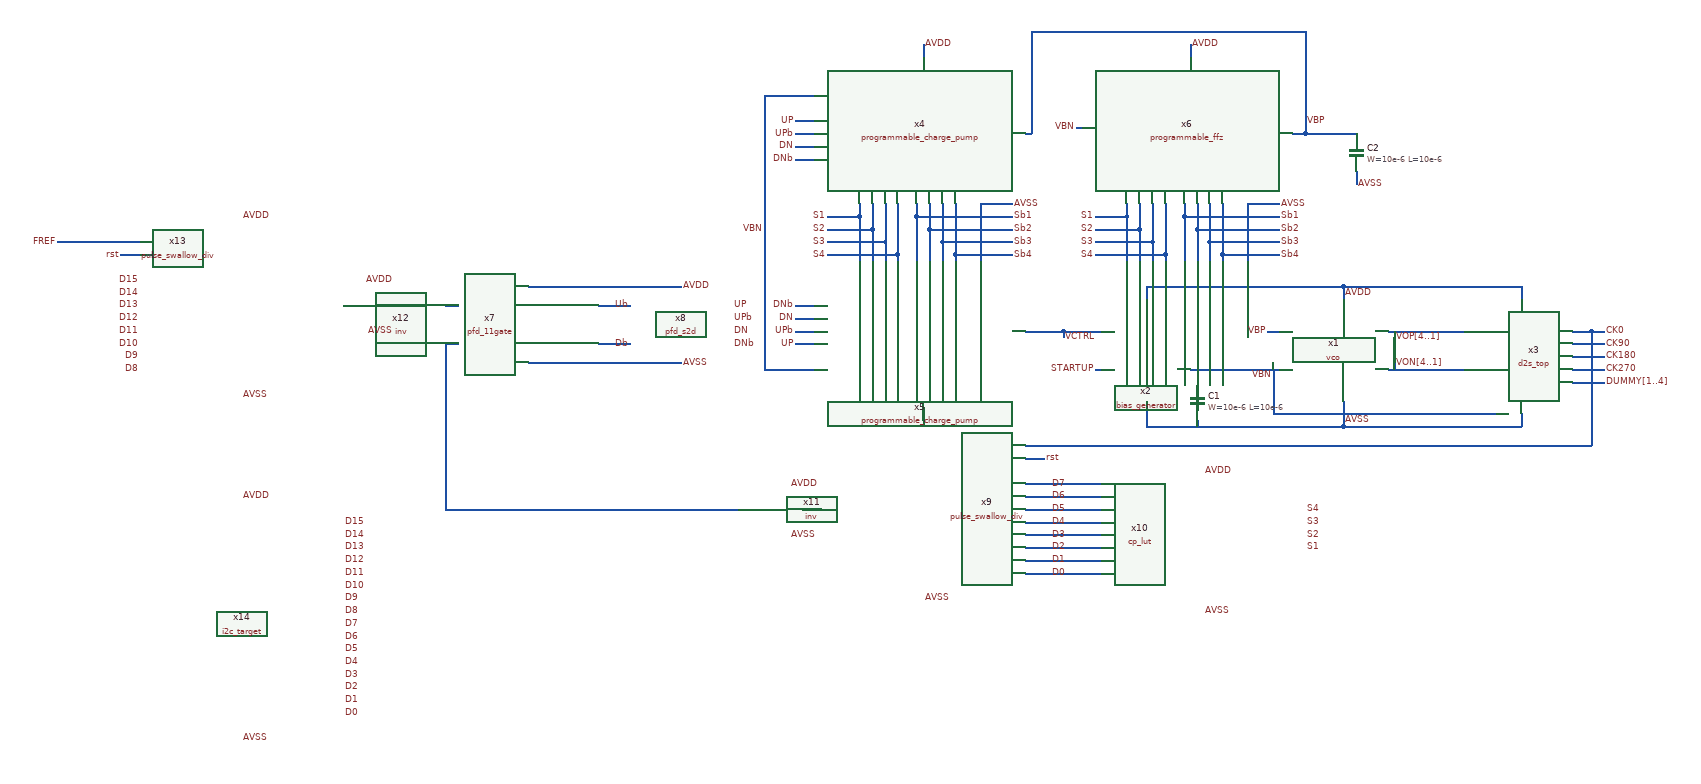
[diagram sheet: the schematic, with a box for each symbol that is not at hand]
v {xschem version=3.4.8RC file_version=1.3}
G {}
K {}
V {}
S {}
F {}
E {}
N 1640 -770 1700 -770 {lab=VCTRL}
N 1910 -710 1980 -710 {lab=VBN}
N 1970 -710 1970 -690 {lab=VBN}
N 2080 -660 2080 -620 {lab=AVSS}
N 1840 -620 2080 -620 {lab=AVSS}
N 1770 -660 1770 -620 {lab=AVSS}
N 2080 -840 2080 -820 {lab=AVDD}
N 1770 -840 1770 -820 {lab=AVDD}
N 1690 -710 1700 -710 {lab=STARTUP}
N 1840 -840 2080 -840 {lab=AVDD}
N 1630 -770 1640 -770 {lab=VCTRL}
N 1620 -770 1630 -770 {lab=VCTRL}
N 1960 -770 1980 -770 {lab=VBP}
N 1640 -770 1640 -760 {lab=VCTRL}
N 2150 -770 2270 -770 {lab=VOP[4..1]}
N 2150 -710 2270 -710 {lab=VON[4..1]}
N 2160 -720 2160 -710 {lab=VON[4..1]}
N 2160 -770 2160 -760 {lab=VOP[4..1]}
N 2360 -840 2360 -820 {lab=AVDD}
N 2080 -840 2360 -840 {lab=AVDD}
N 2360 -640 2360 -620 {lab=AVSS}
N 2080 -620 2360 -620 {lab=AVSS}
N 1770 -620 1840 -620 {lab=AVSS}
N 1850 -630 1850 -620 {lab=AVSS}
N 1840 -710 1910 -710 {lab=VBN}
N 1850 -710 1850 -690 {lab=VBN}
N 1970 -690 1970 -640 {lab=VBN}
N 1970 -640 2320 -640 {lab=VBN}
N 1770 -840 1840 -840 {lab=AVDD}
N 1270 -950 1320 -950 {lab=S1}
N 1270 -930 1340 -930 {lab=S2}
N 1270 -910 1360 -910 {lab=S3}
N 1270 -890 1380 -890 {lab=S4}
N 1510 -970 1560 -970 {lab=AVSS}
N 1470 -890 1560 -890 {lab=Sb4}
N 1450 -910 1560 -910 {lab=Sb3}
N 1430 -930 1560 -930 {lab=Sb2}
N 1410 -950 1560 -950 {lab=Sb1}
N 1230 -1140 1250 -1140 {lab=VBN}
N 1230 -710 1250 -710 {lab=VBN}
N 1220 -1040 1250 -1040 {lab=DNb}
N 1220 -1080 1250 -1080 {lab=UPb}
N 1220 -1060 1250 -1060 {lab=DN}
N 1220 -1100 1250 -1100 {lab=UP}
N 1220 -810 1250 -810 {lab=DNb}
N 1220 -770 1250 -770 {lab=UPb}
N 1220 -790 1250 -790 {lab=DN}
N 1220 -750 1250 -750 {lab=UP}
N 1420 -1220 1420 -1200 {lab=AVDD}
N 1420 -650 1420 -630 {lab=AVDD}
N 1510 -970 1510 -880 {lab=AVSS}
N 1170 -1140 1230 -1140 {lab=VBN}
N 1170 -1140 1170 -710 {lab=VBN}
N 1170 -710 1230 -710 {lab=VBN}
N 2020 -1160 2020 -1080 {lab=VBP}
N 1410 -950 1410 -880 {lab=Sb1}
N 1430 -930 1430 -880 {lab=Sb2}
N 1450 -910 1450 -880 {lab=Sb3}
N 1470 -890 1470 -880 {lab=Sb4}
N 1320 -950 1320 -880 {lab=S1}
N 1340 -930 1340 -880 {lab=S2}
N 1360 -910 1360 -880 {lab=S3}
N 1380 -890 1380 -880 {lab=S4}
N 1380 -970 1380 -890 {lab=S4}
N 1360 -970 1360 -910 {lab=S3}
N 1340 -970 1340 -930 {lab=S2}
N 1320 -970 1320 -950 {lab=S1}
N 1410 -970 1410 -950 {lab=Sb1}
N 1430 -970 1430 -930 {lab=Sb2}
N 1450 -970 1450 -910 {lab=Sb3}
N 1470 -970 1470 -890 {lab=Sb4}
N 1690 -950 1740 -950 {lab=S1}
N 1690 -930 1760 -930 {lab=S2}
N 1690 -910 1780 -910 {lab=S3}
N 1690 -890 1800 -890 {lab=S4}
N 1930 -970 1980 -970 {lab=AVSS}
N 1890 -890 1980 -890 {lab=Sb4}
N 1870 -910 1980 -910 {lab=Sb3}
N 1850 -930 1980 -930 {lab=Sb2}
N 1830 -950 1980 -950 {lab=Sb1}
N 1930 -970 1930 -880 {lab=AVSS}
N 1830 -950 1830 -880 {lab=Sb1}
N 1850 -930 1850 -880 {lab=Sb2}
N 1870 -910 1870 -880 {lab=Sb3}
N 1890 -890 1890 -880 {lab=Sb4}
N 1740 -950 1740 -880 {lab=S1}
N 1760 -930 1760 -880 {lab=S2}
N 1780 -910 1780 -880 {lab=S3}
N 1800 -890 1800 -880 {lab=S4}
N 1800 -970 1800 -890 {lab=S4}
N 1780 -970 1780 -910 {lab=S3}
N 1760 -970 1760 -930 {lab=S2}
N 1740 -970 1740 -950 {lab=S1}
N 1830 -970 1830 -950 {lab=Sb1}
N 1850 -970 1850 -930 {lab=Sb2}
N 1870 -970 1870 -910 {lab=Sb3}
N 1890 -970 1890 -890 {lab=Sb4}
N 2000 -1080 2020 -1080 {lab=VBP}
N 1590 -1090 1590 -1080 {lab=VBP}
N 1580 -1080 1590 -1080 {lab=VBP}
N 2020 -1240 2020 -1220 {lab=VBP}
N 1590 -1240 2020 -1240 {lab=VBP}
N 1590 -1240 1590 -1090 {lab=VBP}
N 1840 -1220 1840 -1200 {lab=AVDD}
N 1660 -1090 1670 -1090 {lab=VBN}
N 2020 -1220 2020 -1160 {lab=VBP}
N 1580 -770 1620 -770 {lab=VCTRL}
N 910 -810 960 -810 {lab=Ub}
N 910 -750 960 -750 {lab=Db}
N 800 -840 1040 -840 {lab=AVDD}
N 800 -720 1040 -720 {lab=AVSS}
N 1580 -590 1610 -590 {lab=CK0}
N 1580 -570 1610 -570 {lab=rst}
N 1580 -530 1700 -530 {lab=D7}
N 1580 -510 1700 -510 {lab=D6}
N 1580 -490 1700 -490 {lab=D5}
N 1580 -470 1700 -470 {lab=D4}
N 1580 -450 1700 -450 {lab=D3}
N 1580 -430 1700 -430 {lab=D2}
N 1580 -410 1700 -410 {lab=D1}
N 1580 -390 1700 -390 {lab=D0}
N 1610 -590 2470 -590 {lab=CK0}
N 2470 -770 2470 -590 {lab=CK0}
N 2440 -770 2470 -770 {lab=CK0}
N 1230 -490 1260 -490 {lab=#net1}
N 670 -490 1130 -490 {lab=#net2}
N 670 -750 670 -490 {lab=#net2}
N 670 -750 690 -750 {lab=#net2}
N 670 -810 690 -810 {lab=#net3}
N 2020 -1080 2100 -1080 {lab=VBP}
N 2100 -1020 2100 -1000 {lab=AVSS}
N 510 -810 570 -810 {lab=#net4}
N 60 -910 190 -910 {lab=FREF}
N 160 -890 190 -890 {lab=rst}
N 2440 -750 2490 -750 {lab=CK90}
N 2470 -770 2490 -770 {lab=CK0}
N 2440 -730 2490 -730 {lab=CK180}
N 2440 -710 2490 -710 {lab=CK270}
N 2440 -690 2490 -690 {lab=DUMMY[1..4]}
C {libs/core_analog/vco/vco.sym} 2080 -740 0 0 {name=x1}
C {libs/core_analog/bias_generator/bias_generator.sym} 1770 -740 0 0 {name=x2}
C {lab_pin.sym} 2080 -630 0 1 {name=p9 sig_type=std_logic lab=AVSS}
C {lab_pin.sym} 1690 -710 0 0 {name=p11 sig_type=std_logic lab=STARTUP}
C {lab_pin.sym} 2160 -760 2 0 {name=p13 sig_type=std_logic lab=VOP[4..1]}
C {lab_pin.sym} 2160 -720 2 0 {name=p14 sig_type=std_logic lab=VON[4..1]}
C {lab_pin.sym} 2080 -830 0 1 {name=p41 sig_type=std_logic lab=AVDD}
C {lab_pin.sym} 1970 -700 0 0 {name=p38 sig_type=std_logic lab=VBN}
C {lab_pin.sym} 1960 -770 0 0 {name=p39 sig_type=std_logic lab=VBP}
C {lab_pin.sym} 1640 -760 0 1 {name=p42 sig_type=std_logic lab=VCTRL}
C {symbols/cap_mim_2f0fF.sym} 1850 -660 2 1 {name=C1
W=10e-6
L=10e-6
model=cap_mim_2f0fF
spiceprefix=X
m=50}
C {libs/core_analog/d2s_top/d2s_top.sym} 2360 -740 0 0 {name=x3}
C {lab_pin.sym} 1170 -930 0 0 {name=p1 sig_type=std_logic lab=VBN}
C {lab_pin.sym} 1420 -1220 0 1 {name=p43 sig_type=std_logic lab=AVDD}
C {lab_wire.sym} 1220 -1100 0 0 {name=p47 sig_type=std_logic lab=UP}
C {lab_wire.sym} 1220 -1060 0 0 {name=p48 sig_type=std_logic lab=DN}
C {lab_wire.sym} 1220 -1040 0 0 {name=p49 sig_type=std_logic lab=DNb}
C {lab_wire.sym} 1220 -1080 0 0 {name=p50 sig_type=std_logic lab=UPb}
C {lab_wire.sym} 1220 -750 2 1 {name=p51 sig_type=std_logic lab=UP}
C {lab_wire.sym} 1220 -790 2 1 {name=p52 sig_type=std_logic lab=DN}
C {lab_wire.sym} 1220 -810 2 1 {name=p53 sig_type=std_logic lab=DNb}
C {lab_wire.sym} 1220 -770 2 1 {name=p54 sig_type=std_logic lab=UPb}
C {lab_pin.sym} 1420 -640 2 0 {name=p17 sig_type=std_logic lab=AVDD}
C {lab_pin.sym} 1560 -970 0 1 {name=p46 sig_type=std_logic lab=AVSS}
C {lab_pin.sym} 1270 -950 2 1 {name=p59 sig_type=std_logic lab=S1}
C {lab_pin.sym} 1270 -930 2 1 {name=p60 sig_type=std_logic lab=S2}
C {lab_pin.sym} 1270 -910 2 1 {name=p61 sig_type=std_logic lab=S3}
C {lab_pin.sym} 1270 -890 2 1 {name=p62 sig_type=std_logic lab=S4}
C {lab_pin.sym} 1980 -970 0 1 {name=p63 sig_type=std_logic lab=AVSS}
C {lab_pin.sym} 1980 -950 2 0 {name=p64 sig_type=std_logic lab=Sb1}
C {lab_pin.sym} 1690 -950 2 1 {name=p68 sig_type=std_logic lab=S1}
C {lab_pin.sym} 1690 -930 2 1 {name=p69 sig_type=std_logic lab=S2}
C {lab_pin.sym} 1690 -910 2 1 {name=p70 sig_type=std_logic lab=S3}
C {lab_pin.sym} 1690 -890 2 1 {name=p71 sig_type=std_logic lab=S4}
C {lab_pin.sym} 2020 -1100 0 1 {name=p72 sig_type=std_logic lab=VBP}
C {lab_pin.sym} 1840 -1220 0 1 {name=p73 sig_type=std_logic lab=AVDD}
C {lab_pin.sym} 1660 -1090 0 0 {name=p74 sig_type=std_logic lab=VBN}
C {lab_pin.sym} 1980 -930 2 0 {name=p65 sig_type=std_logic lab=Sb2}
C {lab_pin.sym} 1980 -910 2 0 {name=p66 sig_type=std_logic lab=Sb3}
C {lab_pin.sym} 1980 -890 2 0 {name=p67 sig_type=std_logic lab=Sb4}
C {lab_pin.sym} 1560 -950 2 0 {name=p105 sig_type=std_logic lab=Sb1}
C {lab_pin.sym} 1560 -930 2 0 {name=p106 sig_type=std_logic lab=Sb2}
C {lab_pin.sym} 1560 -910 2 0 {name=p107 sig_type=std_logic lab=Sb3}
C {lab_pin.sym} 1560 -890 2 0 {name=p109 sig_type=std_logic lab=Sb4}
C {libs/core_analog/programmable_charge_pump/programmable_charge_pump.sym} 1420 -1080 0 0 {name=x4}
C {libs/core_analog/programmable_charge_pump/programmable_charge_pump.sym} 1420 -770 2 1 {name=x5}
C {libs/core_analog/programmable_ffz/programmable_ffz.sym} 1840 -1090 0 0 {name=x6}
C {libs/core_analog/pfd/pfd_11gate.sym} 800 -780 0 0 {name=x7}
C {lab_wire.sym} 960 -810 0 0 {name=p4 sig_type=std_logic lab=Ub}
C {lab_wire.sym} 960 -750 0 0 {name=p5 sig_type=std_logic lab=Db}
C {libs/core_analog/pfd_s2d/pfd_s2d.sym} 1040 -780 0 0 {name=x8}
C {lab_wire.sym} 1120 -810 0 1 {name=p10 sig_type=std_logic lab=UP}
C {lab_wire.sym} 1120 -770 0 1 {name=p2 sig_type=std_logic lab=DN}
C {lab_wire.sym} 1120 -790 0 1 {name=p12 sig_type=std_logic lab=UPb}
C {lab_wire.sym} 1120 -750 0 1 {name=p3 sig_type=std_logic lab=DNb}
C {libs/core_analog/pulse_swallow_div/src/pulse_swallow_div.sym} 1420 -490 0 1 {name=x9}
C {lab_pin.sym} 1610 -570 0 1 {name=p6 sig_type=std_logic lab=rst}
C {libs/core_analog/lut/cp_lut.sym} 1860 -370 0 0 {name=x10}
C {lab_pin.sym} 1860 -550 0 1 {name=p93 sig_type=std_logic lab=AVDD}
C {lab_pin.sym} 2020 -430 2 0 {name=p99 sig_type=std_logic lab=S1}
C {lab_pin.sym} 2020 -450 2 0 {name=p102 sig_type=std_logic lab=S2}
C {lab_pin.sym} 2020 -470 2 0 {name=p103 sig_type=std_logic lab=S3}
C {lab_pin.sym} 2020 -490 2 0 {name=p104 sig_type=std_logic lab=S4}
C {lab_pin.sym} 1620 -530 0 1 {name=p55 sig_type=std_logic lab=D7}
C {lab_pin.sym} 1620 -510 0 1 {name=p56 sig_type=std_logic lab=D6}
C {lab_pin.sym} 1620 -490 0 1 {name=p57 sig_type=std_logic lab=D5}
C {lab_pin.sym} 1620 -470 0 1 {name=p58 sig_type=std_logic lab=D4}
C {lab_pin.sym} 1620 -450 0 1 {name=p110 sig_type=std_logic lab=D3}
C {lab_pin.sym} 1620 -430 0 1 {name=p111 sig_type=std_logic lab=D2}
C {lab_pin.sym} 1620 -410 0 1 {name=p112 sig_type=std_logic lab=D1}
C {lab_pin.sym} 1620 -390 0 1 {name=p113 sig_type=std_logic lab=D0}
C {libs/core_analog/inv/inv.sym} 1190 -490 0 1 {name=x11}
C {libs/core_analog/inv/inv.sym} 610 -810 0 0 {name=x12}
C {symbols/cap_mim_2f0fF.sym} 2100 -1050 2 1 {name=C2
W=10e-6
L=10e-6
model=cap_mim_2f0fF
spiceprefix=X
m=50}
C {lab_pin.sym} 2100 -1000 0 1 {name=p7 sig_type=std_logic lab=AVSS}
C {lab_pin.sym} 1210 -530 2 0 {name=p8 sig_type=std_logic lab=AVDD}
C {lab_pin.sym} 1860 -330 0 1 {name=p15 sig_type=std_logic lab=AVSS}
C {lab_pin.sym} 1420 -350 0 1 {name=p16 sig_type=std_logic lab=AVSS}
C {lab_pin.sym} 1210 -450 0 1 {name=p18 sig_type=std_logic lab=AVSS}
C {lab_pin.sym} 590 -850 2 1 {name=p19 sig_type=std_logic lab=AVDD}
C {lab_pin.sym} 590 -770 0 0 {name=p20 sig_type=std_logic lab=AVSS}
C {libs/core_analog/pulse_swallow_div/src/pulse_swallow_div.sym} 350 -810 0 0 {name=x13}
C {libs/core_analog/I2C/i2c_target.sym} 350 -310 0 0 {name=x14}
C {lab_pin.sym} 350 -950 2 0 {name=p21 sig_type=std_logic lab=AVDD}
C {lab_pin.sym} 350 -670 0 1 {name=p22 sig_type=std_logic lab=AVSS}
C {lab_pin.sym} 160 -890 0 0 {name=p23 sig_type=std_logic lab=rst}
C {lab_pin.sym} 510 -310 0 1 {name=p24 sig_type=std_logic lab=D7}
C {lab_pin.sym} 510 -290 0 1 {name=p25 sig_type=std_logic lab=D6}
C {lab_pin.sym} 510 -270 0 1 {name=p26 sig_type=std_logic lab=D5}
C {lab_pin.sym} 510 -250 0 1 {name=p27 sig_type=std_logic lab=D4}
C {lab_pin.sym} 510 -230 0 1 {name=p28 sig_type=std_logic lab=D3}
C {lab_pin.sym} 510 -210 0 1 {name=p29 sig_type=std_logic lab=D2}
C {lab_pin.sym} 510 -190 0 1 {name=p30 sig_type=std_logic lab=D1}
C {lab_pin.sym} 510 -170 0 1 {name=p31 sig_type=std_logic lab=D0}
C {lab_pin.sym} 510 -470 0 1 {name=p32 sig_type=std_logic lab=D15}
C {lab_pin.sym} 510 -450 0 1 {name=p33 sig_type=std_logic lab=D14}
C {lab_pin.sym} 510 -430 0 1 {name=p34 sig_type=std_logic lab=D13}
C {lab_pin.sym} 510 -410 0 1 {name=p35 sig_type=std_logic lab=D12}
C {lab_pin.sym} 510 -390 0 1 {name=p36 sig_type=std_logic lab=D11}
C {lab_pin.sym} 510 -370 0 1 {name=p37 sig_type=std_logic lab=D10}
C {lab_pin.sym} 510 -350 0 1 {name=p40 sig_type=std_logic lab=D9}
C {lab_pin.sym} 510 -330 0 1 {name=p44 sig_type=std_logic lab=D8}
C {lab_pin.sym} 350 -130 0 1 {name=p45 sig_type=std_logic lab=AVSS}
C {lab_pin.sym} 350 -510 2 0 {name=p75 sig_type=std_logic lab=AVDD}
C {lab_pin.sym} 190 -850 0 0 {name=p76 sig_type=std_logic lab=D15}
C {lab_pin.sym} 190 -830 0 0 {name=p77 sig_type=std_logic lab=D14}
C {lab_pin.sym} 190 -810 0 0 {name=p78 sig_type=std_logic lab=D13}
C {lab_pin.sym} 190 -790 0 0 {name=p79 sig_type=std_logic lab=D12}
C {lab_pin.sym} 190 -770 0 0 {name=p80 sig_type=std_logic lab=D11}
C {lab_pin.sym} 190 -750 0 0 {name=p81 sig_type=std_logic lab=D10}
C {lab_pin.sym} 190 -730 0 0 {name=p82 sig_type=std_logic lab=D9}
C {lab_pin.sym} 190 -710 0 0 {name=p83 sig_type=std_logic lab=D8}
C {lab_pin.sym} 60 -910 0 0 {name=p84 sig_type=std_logic lab=FREF}
C {lab_pin.sym} 1040 -840 2 0 {name=p85 sig_type=std_logic lab=AVDD}
C {lab_pin.sym} 1040 -720 0 1 {name=p86 sig_type=std_logic lab=AVSS}
C {lab_pin.sym} 2490 -770 0 1 {name=p87 sig_type=std_logic lab=CK0}
C {lab_pin.sym} 2490 -750 0 1 {name=p88 sig_type=std_logic lab=CK90}
C {lab_pin.sym} 2490 -730 0 1 {name=p89 sig_type=std_logic lab=CK180}
C {lab_pin.sym} 2490 -710 0 1 {name=p90 sig_type=std_logic lab=CK270}
C {lab_pin.sym} 2490 -690 0 1 {name=p91 sig_type=std_logic lab=DUMMY[1..4]}
